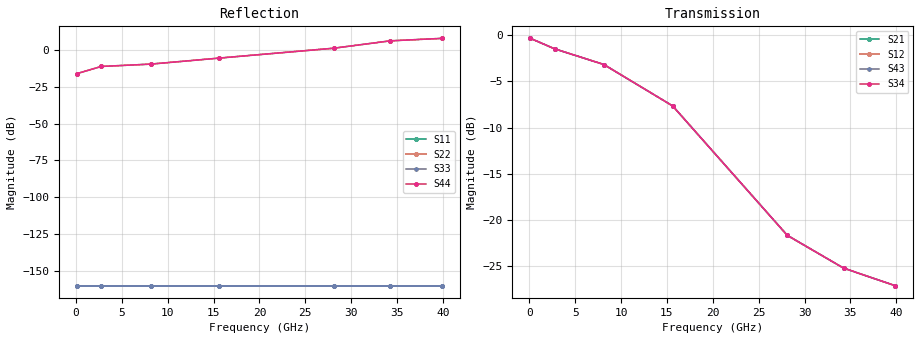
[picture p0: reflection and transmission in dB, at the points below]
! 26-Jun-2017 15:41:59
# Hz S RI R 50
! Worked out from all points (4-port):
!   319 points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, 125 MHz to 39.88 GHz, reference 50 ohm
!   strongest paths, dB at 125 MHz, 10 GHz, 20 GHz, 30 GHz, 39.88 GHz:
!     S43: -0.3, -3.8, -12.3, -23.3, -27.2
!     S21: -0.3, -3.8, -12.3, -23.3, -27.2
!     S42: -, -, -, -, -
!     S41: -, -, -, -, -
!     S32: -, -, -, -, -
!     S31: -, -, -, -, -
!   lowest |S11| = - dB at 125 MHz (marker M1), VSWR 1.00, Z = 50 + j0 ohm
!   |S11| at or under -10 dB: start of sweep to end of sweep
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1.25e8  0 0  0.9634 -0.0258  0 0  0 0
        0.9634 -0.0258  -0.1586 -0.00737  0 0  0 0
        0 0  0 0  0 0  0.9634 -0.0258
        0 0  0 0  0.9634 -0.0258  -0.1586 -0.00737
2.75e9  0 0  0.753 -0.3856  0 0  0 0
        0.753 -0.3856  -0.2714 -0.0548  0 0  0 0
        0 0  0 0  0 0  0.753 -0.3856
        0 0  0 0  0.753 -0.3856  -0.2714 -0.0548
8.125e9  0 0  0.2928 -0.6304  0 0  0 0
         0.2928 -0.6304  -0.3249 0.068  0 0  0 0
         0 0  0 0  0 0  0.2928 -0.6304
         0 0  0 0  0.2928 -0.6304  -0.3249 0.068
1.5625e10  0 0  -0.2645 -0.319  0 0  0 0
           -0.2645 -0.319  -0.4937 0.2002  0 0  0 0
           0 0  0 0  0 0  -0.2645 -0.319
           0 0  0 0  -0.2645 -0.319  -0.4937 0.2002
2.8125e10  0 0  -0.0247 0.0784  0 0  0 0
           -0.0247 0.0784  -0.4124 1.078  0 0  0 0
           0 0  0 0  0 0  -0.0247 0.0784
           0 0  0 0  -0.0247 0.0784  -0.4124 1.078
3.425e10  0 0  0.0447 0.0314  0 0  0 0
          0.0447 0.0314  -0.8144 1.88  0 0  0 0
          0 0  0 0  0 0  0.0447 0.0314
          0 0  0 0  0.0447 0.0314  -0.8144 1.88
3.9875e10  0 0  0.0414 -0.0144  0 0  0 0
           0.0414 -0.0144  -1.172 2.193  0 0  0 0
           0 0  0 0  0 0  0.0414 -0.0144
           0 0  0 0  0.0414 -0.0144  -1.172 2.193
